VERSION 5.7 ;
  NOWIREEXTENSIONATPIN ON ;
  DIVIDERCHAR "/" ;
  BUSBITCHARS "[]" ;
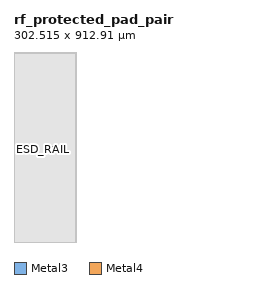
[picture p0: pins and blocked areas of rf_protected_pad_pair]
MACRO rf_protected_pad_pair
  CLASS BLOCK ;
  FOREIGN rf_protected_pad_pair ;
  ORIGIN 0.055 0.000 ;
  SIZE 302.515 BY 912.910 ;
  PIN VSS
    USE GROUND ;
    PORT
      LAYER Metal3 ;
        RECT 137.850 443.850 138.150 444.150 ;
      LAYER Metal4 ;
        RECT 137.850 443.850 138.150 444.150 ;
    END
  END VSS
  PIN ESD_RAIL
    ANTENNAGATEAREA 8400.000000 ;
    ANTENNADIFFAREA 5703.652832 ;
    PORT
      LAYER Metal3 ;
        RECT 129.850 443.850 130.150 444.150 ;
      LAYER Metal4 ;
        RECT 129.850 443.850 130.150 444.150 ;
    END
  END ESD_RAIL
  PIN PAD_P
    ANTENNADIFFAREA 180.000000 ;
    PORT
      LAYER Metal3 ;
        RECT 185.000 443.000 187.000 459.850 ;
    END
  END PAD_P
  PIN ATB_ESD_RAIL
    PORT
      LAYER Metal3 ;
        RECT 91.180 438.000 91.980 441.450 ;
    END
  END ATB_ESD_RAIL
  OBS
      LAYER Nwell ;
        RECT 3.005 440.200 302.460 910.735 ;
      LAYER Metal1 ;
        RECT 0.050 438.200 302.235 912.910 ;
      LAYER Metal2 ;
        RECT -0.055 0.000 302.235 912.910 ;
      LAYER Metal3 ;
        RECT 0.050 460.150 300.700 912.910 ;
        RECT 0.050 444.450 184.700 460.150 ;
        RECT 0.050 443.550 129.550 444.450 ;
        RECT 130.450 443.550 137.550 444.450 ;
        RECT 138.450 443.550 184.700 444.450 ;
        RECT 0.050 442.700 184.700 443.550 ;
        RECT 187.300 442.700 300.700 460.150 ;
        RECT 0.050 441.750 300.700 442.700 ;
        RECT 0.050 437.700 90.880 441.750 ;
        RECT 92.280 437.700 300.700 441.750 ;
        RECT 0.050 0.000 300.700 437.700 ;
      LAYER Metal4 ;
        RECT 3.500 0.000 294.000 906.575 ;
      LAYER Metal5 ;
        RECT 2.055 0.000 294.000 906.575 ;
  END
END rf_protected_pad_pair
END LIBRARY

